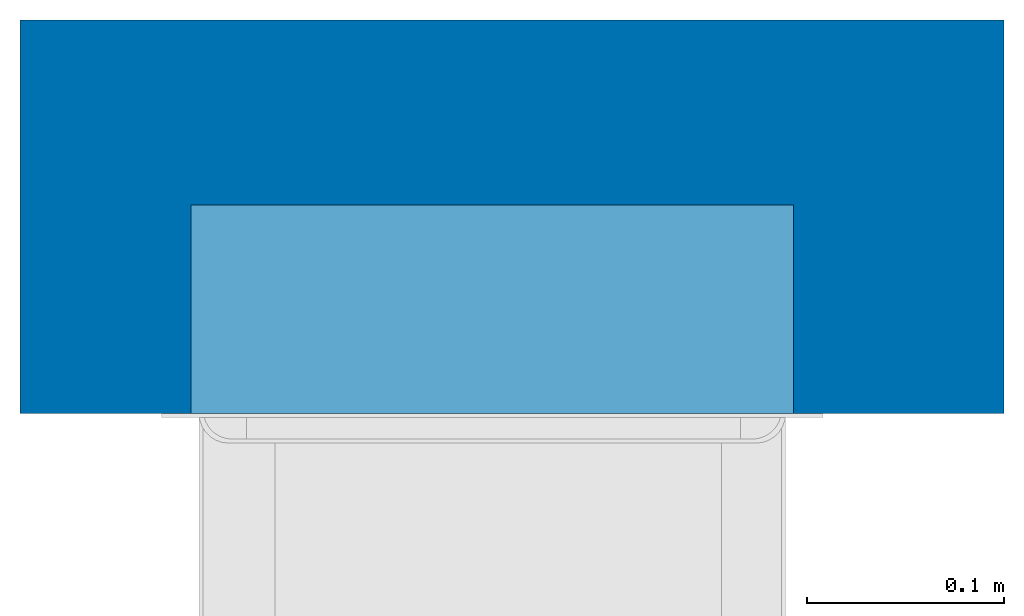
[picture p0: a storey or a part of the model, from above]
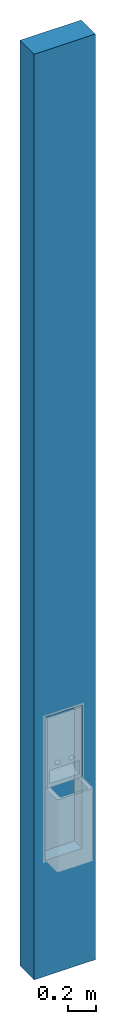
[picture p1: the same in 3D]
Properties of the parts of a building model (IFC2X3)

# File
Description: ViewDefinition [CoordinationView_V2.0], RevitIdentifiers [VersionGUID: 5675a4a3-ebdb-43aa-8d4a-8bdf9b4e5b8a, NumberOfSaves: 0], CoordinateReference [CoordinateBase: Shared Coordinates]
File name: Project Number
Time: 2025-11-19T21:20:19+02:00
Written by: ODA SDAI 24.6
Made in: Autodesk Revit 24.2.0.63 (ENU) - IFC 24.2.0.63

# IfcProject, Project Number
LongName: Project Name; Phase: Project Status

# IfcSite, Default
RefLatitude: 42, 21, 31, 181945; RefLongitude: -71, -3, -24, -263305; RefElevation: 0 mm

# IfcBuilding
Pset_BuildingCommon - NumberOfStoreys: 1

# IfcBuildingStorey: Level:8mm Head (2)
Pset_AirSideSystemInformation - sets with these values: 2
Name | LongName = Name | Elevation (mm)
Level 1 | Level 1 | 0
Level 2 | Level 2 | 4000

# IfcFurnishingElement: 14710008103:d_line_Washroom_RecessedSanitaryPanels_PaperTowelDispenser__ProtrudedWasteBin_PanelSize8, 14710008103:d_line_Washroom_RecessedSanitaryPanels_PaperTowelDispenser__ProtrudedWasteBin_PanelSize8:237458
In: Level 1
Type - Material: <Unnamed>
Type - Pset_ElementShading - Color: Silver
Type - Pset_FurnitureTypeCommon - Description: Recessed sanitary panel with paper towel dispenser and a waste bin; Style: Recessed; NominalHeight: 1272 mm; NominalDepth: 121 mm; MainColor: Silver
Type - Pset_ManufacturerTypeInformation - ModelReference: 45-35-72/344; Manufacturer: info@dline.com
Type - Pset_ProductRequirements - Name: d_line_Washroom_RecessedSanitaryPanels_PaperTowelDispenser__ProtrudedWasteBin_PanelSize8
Pset_ManufacturerOccurrence - BarCode: n/a; SerialNumber: n/a
Pset_QuantityTakeOff - Reference: d_line_Washroom_RecessedSanitaryPanels_PaperTowelDispenser__ProtrudedWasteBin_PanelSize8

# IfcOpeningElement: Opening (3)
In: Level 1
Pset_ManufacturerOccurrence - BarCode: n/a; SerialNumber: n/a
Pset_OpeningElementCommon - Reference: d_line_Washroom_RecessedSanitaryPanels_PaperTowelDispenser__ProtrudedWasteBin_PanelSize8; sets with these values: 2
Name (14710008103:d_line_Washroom_RecessedSanitaryPanels_PaperTowelDispenser__ProtrudedWasteBin_PanelSize8:237458:...)
1
2
3

# IfcOpeningElement: Recess, Basic Wall:Generic - 200mm:236201
In: Level 1
Pset_ManufacturerOccurrence - BarCode: n/a; SerialNumber: n/a
Pset_OpeningElementCommon - Reference: d_line_Washroom_RecessedSanitaryPanels_PaperTowelDispenser__ProtrudedWasteBin_PanelSize8; sets with these values: 2

# IfcWallStandardCase: Basic Wall:Generic - 200mm, Basic Wall:Generic - 200mm:236201
In: Level 1
Type - PredefinedType: STANDARD; Material: Default Wall 200 mm
Type - Pset_WallCommon - IsExternal: yes
Pset_QuantityTakeOff - Reference: Generic - 200mm; sets with these values: 2
Pset_WallCommon - Reference: Generic - 200mm; ExtendToStructure: no; LoadBearing: no
